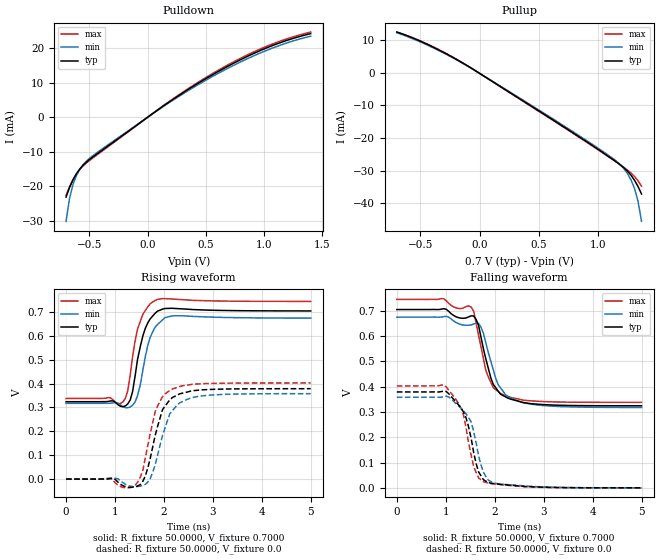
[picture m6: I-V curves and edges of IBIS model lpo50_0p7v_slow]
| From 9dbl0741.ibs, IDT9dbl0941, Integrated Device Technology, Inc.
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|   Model lpo50_0p7v_slow
[Model]  lpo50_0p7v_slow
Model_type Output
Polarity   Non-Inverting
Vmeas =  0.4000V
Cref =   2.0000pF
Rref =   0.0
Vref =   0.4000V
C_comp   1.1000pF   1.0000pF   1.2000pF
[Temperature Range]   27.0000   70.0000   0.0
[Voltage Range]   0.7000V   0.6700V   0.7400V
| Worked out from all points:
|   slope of the pulldown table from 0 to 0.105 V, typ, clamps not added: 41.3 ohm
|   slope of the pullup table from 0 to 0.105 V, typ, clamps not added: 43.4 ohm
|   rising waveform, R_fixture 50.0000, V_fixture 0.7000: 20-80 % time 228ps typ, 231ps min, 222ps max; typ from 0.324 V to 0.705 V
|   rising waveform, R_fixture 50.0000, V_fixture 0.0: 20-80 % time 306ps typ, 336ps min, 300ps max; typ from 0 V to 0.379 V
|   falling waveform, R_fixture 50.0000, V_fixture 0.7000: 20-80 % time 319ps typ, 363ps min, 309ps max; typ from 0.704 V to 0.324 V
|   falling waveform, R_fixture 50.0000, V_fixture 0.0: 20-80 % time 299ps typ, 317ps min, 285ps max; typ from 0.379 V to 0 V
[Pulldown]
|Voltage   I(typ)   I(min)   I(max)
-700mV    -23.07mA   -30.06mA   -22.55mA
-670mV    -20.3mA    -23.39mA   -20.06mA
-640mV    -18.07mA   -19.37mA   -17.97mA
-610mV    -16.28mA   -16.77mA   -16.3mA
-580mV    -14.86mA   -14.94mA   -14.98mA
-550mV    -13.73mA   -13.58mA   -13.94mA
-460mV    -11.23mA   -10.85mA   -11.51mA
200mV     4.757mA    4.547mA    4.904mA
590mV     12.91mA    12.39mA    13.27mA
980mV     19.46mA    18.75mA    19.92mA
1.19V     22.15mA    21.42mA    22.6mA
1.4V      24.16mA    23.42mA    24.62mA
[Pullup]
|Voltage   I(typ)   I(min)   I(max)
-700mV    12.47mA    12.25mA    12.46mA
-430mV    8.493mA    8.28mA     8.576mA
-160mV    3.337mA    3.235mA    3.395mA
590mV     -13.76mA   -13.46mA   -13.9mA
920mV     -21.51mA   -21.16mA   -21.66mA
1.13V     -26.66mA   -26.37mA   -26.76mA
1.22V     -29.12mA   -29.37mA   -29.03mA
1.25V     -30.13mA   -30.86mA   -29.84mA
1.28V     -31.38mA   -32.79mA   -30.73mA
1.31V     -32.94mA   -35.43mA   -31.79mA
1.34V     -34.86mA   -39.33mA   -33.12mA
1.37V     -37.19mA   -45.56mA   -34.8mA
[Ramp]
| variable   typ   min   max
dV/dt_r  0.2273/0.3063n   0.2148/0.3359n   0.2417/0.2998n
dV/dt_f  0.2282/0.3187n   0.2141/0.3633n   0.2441/0.3088n
R_load = 50.0000
[Rising Waveform]
R_fixture= 50.0000
V_fixture= 0.7000
V_fixture_min= 0.6700
V_fixture_max= 0.7400
|time   V(typ)   V(min)   V(max)
0s        324.2mV    317.4mV    337.8mV
960ps     327.6mV    319.7mV    332mV
1.16ns    303.4mV    303.5mV    322.9mV
1.26ns    314.7mV    299mV      369.9mV
1.31ns    331.1mV    302mV      434.7mV
1.46ns    500.6mV    349.2mV    627.8mV
1.67ns    654.5mV    560.4mV    721.7mV
1.87ns    704mV      648mV      753mV
2.22ns    715.1mV    684.5mV    753.9mV
5ns       704.6mV    674.6mV    744.6mV
[Rising Waveform]
R_fixture= 50.0000
V_fixture= 0.0
V_fixture_min= 0.0
V_fixture_max= 0.0
|time   V(typ)   V(min)   V(max)
0s        578.5nV    0V         711.6nV
1.01ns    -2.639mV   3.765mV    -16.71mV
1.41ns    -32.25mV   -32.21mV   -26.14mV
1.57ns    -8.924mV   -26.93mV   38.23mV
1.72ns    86.49mV    1.626mV    190.7mV
1.82ns    182.2mV    58.83mV    281.4mV
1.97ns    290.6mV    181.3mV    345.1mV
2.17ns    341.3mV    286mV      377.4mV
2.73ns    373.1mV    347.5mV    399mV
5ns       378.8mV    358mV      402.8mV
[Falling Waveform]
R_fixture= 50.0000
V_fixture= 0.7000
V_fixture_min= 0.6700
V_fixture_max= 0.7400
|time   V(typ)   V(min)   V(max)
0s        704.5mV    674.4mV    744.6mV
1.01ns    705.5mV    677.7mV    739.3mV
1.52ns    679.7mV    643.6mV    714.2mV
1.57ns    679.1mV    647.6mV    697.9mV
1.67ns    641.8mV    650mV      603.1mV
1.82ns    508.5mV    571.5mV    463.5mV
1.97ns    409.1mV    466.7mV    396.2mV
2.17ns    364.7mV    381.5mV    368.5mV
2.88ns    330.4mV    327.1mV    342.1mV
5ns       324.2mV    317.5mV    337.8mV
[Falling Waveform]
R_fixture= 50.0000
V_fixture= 0.0
V_fixture_min= 0.0
V_fixture_max= 0.0
|time   V(typ)   V(min)   V(max)
0s        378.8mV    358.1mV    402.8mV
1.01ns    380.7mV    362mV      398.3mV
1.36ns    300.6mV    304.6mV    289.3mV
1.52ns    194.4mV    259.9mV    127.8mV
1.57ns    139.1mV    223.2mV    83.96mV
1.67ns    63.07mV    127.3mV    39.32mV
1.77ns    32.14mV    61.52mV    23.67mV
1.87ns    21.91mV    30.24mV    19.06mV
2.17ns    13.02mV    14.09mV    11.72mV
5ns       18.23uV    54.64uV    7.85uV
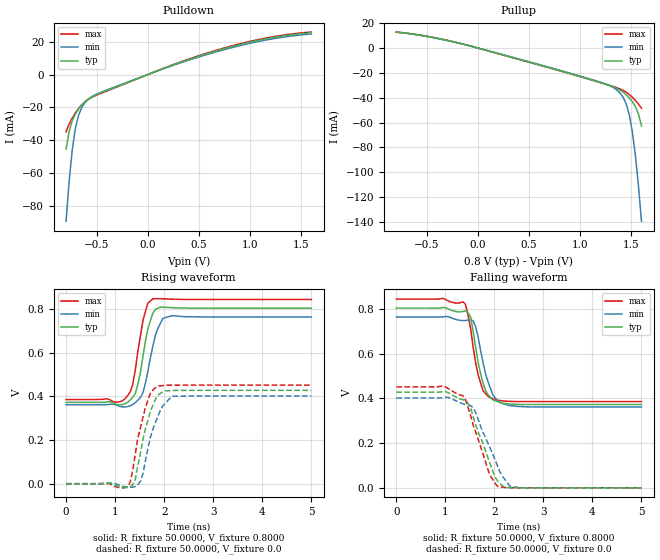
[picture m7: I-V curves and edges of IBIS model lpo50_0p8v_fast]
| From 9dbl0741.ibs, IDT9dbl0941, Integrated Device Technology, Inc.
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|   Model lpo50_0p8v_fast
[Model]  lpo50_0p8v_fast
Model_type Output
Polarity   Non-Inverting
Vmeas =  0.4000V
Cref =   2.0000pF
Rref =   0.0
Vref =   0.4000V
C_comp   1.1000pF   1.0000pF   1.2000pF
[Temperature Range]   27.0000   70.0000   0.0
[Voltage Range]   0.8000V   0.7600V   0.8400V
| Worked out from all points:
|   slope of the pulldown table from 0 to 0.12 V, typ, clamps not added: 41.4 ohm
|   slope of the pullup table from 0 to 0.12 V, typ, clamps not added: 44.4 ohm
|   rising waveform, R_fixture 50.0000, V_fixture 0.8000: 20-80 % time 212ps typ, 229ps min, 196ps max; typ from 0.372 V to 0.804 V
|   rising waveform, R_fixture 50.0000, V_fixture 0.0: 20-80 % time 273ps typ, 299ps min, 256ps max; typ from 0 V to 0.428 V
|   falling waveform, R_fixture 50.0000, V_fixture 0.8000: 20-80 % time 231ps typ, 266ps min, 227ps max; typ from 0.804 V to 0.372 V
|   falling waveform, R_fixture 50.0000, V_fixture 0.0: 20-80 % time 415ps typ, 453ps min, 396ps max; typ from 0.428 V to 0 V
[Pulldown]
|Voltage   I(typ)   I(min)   I(max)
-800mV    -45.52mA   -89.42mA   -34.99mA
-770mV    -34.69mA   -64.98mA   -30.13mA
-740mV    -28.28mA   -46.11mA   -26.53mA
-710mV    -24.18mA   -33.19mA   -23.49mA
-680mV    -21.17mA   -25.25mA   -20.86mA
-650mV    -18.77mA   -20.52mA   -18.63mA
-620mV    -16.84mA   -17.54mA   -16.82mA
-560mV    -14.08mA   -14mA      -14.27mA
100mV     2.426mA    2.317mA    2.503mA
670mV     14.39mA    13.82mA    14.78mA
1.15V     21.69mA    20.96mA    22.14mA
1.6V      25.43mA    24.71mA    25.88mA
[Pullup]
|Voltage   I(typ)   I(min)   I(max)
-800mV    12.69mA    12.68mA    12.51mA
-440mV    8.345mA    8.179mA    8.402mA
-20mV     274.7uA    267.5uA    282.2uA
1.15V     -26.68mA   -26.4mA    -26.75mA
1.36V     -32.54mA   -33.95mA   -32.08mA
1.42V     -35.56mA   -39.7mA    -34.16mA
1.45V     -37.62mA   -44.96mA   -35.6mA
1.48V     -40.1mA    -53.57mA   -37.41mA
1.51V     -43.12mA   -67.09mA   -39.62mA
1.54V     -47.08mA   -86.23mA   -42.2mA
1.57V     -53mA      -110.6mA   -45.14mA
1.6V      -62.75mA   -139.3mA   -48.48mA
[Ramp]
| variable   typ   min   max
dV/dt_r  0.2567/0.2641n   0.2412/0.2994n   0.2710/0.2465n
dV/dt_f  0.2590/0.2314n   0.2414/0.2657n   0.2750/0.2205n
R_load = 50.0000
[Rising Waveform]
R_fixture= 50.0000
V_fixture= 0.8000
V_fixture_min= 0.7600
V_fixture_max= 0.8400
|time   V(typ)   V(min)   V(max)
0s        372.5mV    361.7mV    385.7mV
1.21ns    366.7mV    352.2mV    391.5mV
1.36ns    396.9mV    362.9mV    456.1mV
1.46ns    452.4mV    382mV      601.3mV
1.57ns    586.6mV    418.2mV    749.7mV
1.67ns    712.4mV    516.9mV    828mV
1.77ns    781.9mV    631.5mV    847.1mV
1.97ns    808.9mV    756.4mV    847.4mV
2.17ns    806.4mV    770.1mV    845.2mV
5ns       804.1mV    764mV      844.1mV
[Rising Waveform]
R_fixture= 50.0000
V_fixture= 0.0
V_fixture_min= 0.0
V_fixture_max= 0.0
|time   V(typ)   V(min)   V(max)
0s        0V         0V         0V
1.26ns    -17.13mV   -16.18mV   -11.84mV
1.31ns    -13.73mV   -16.75mV   9.189mV
1.41ns    19.42mV    -13.04mV   134.2mV
1.52ns    145.8mV    12.61mV    260.3mV
1.72ns    331.2mV    213.7mV    414.4mV
1.87ns    405.9mV    308mV      447.2mV
1.97ns    420.8mV    356.2mV    449.4mV
2.17ns    426.9mV    400.6mV    451.4mV
5ns       427.8mV    402mV      451.7mV
[Falling Waveform]
R_fixture= 50.0000
V_fixture= 0.8000
V_fixture_min= 0.7600
V_fixture_max= 0.8400
|time   V(typ)   V(min)   V(max)
0s        804.1mV    764mV      844.1mV
960ps     806.9mV    765.3mV    846.5mV
1.41ns    791.7mV    748.4mV    821.2mV
1.52ns    761.2mV    752mV      706.4mV
1.62ns    627.5mV    718.4mV    557.3mV
1.72ns    510mV      613.5mV    468.3mV
1.87ns    416.2mV    474.9mV    409.4mV
2.02ns    389.1mV    401.9mV    393.7mV
2.53ns    372.9mV    363.4mV    385.8mV
5ns       372.5mV    361.7mV    385.7mV
[Falling Waveform]
R_fixture= 50.0000
V_fixture= 0.0
V_fixture_min= 0.0
V_fixture_max= 0.0
|time   V(typ)   V(min)   V(max)
0s        427.8mV    402mV      451.7mV
960ps     431.2mV    403.4mV    455mV
1.36ns    393.8mV    375.9mV    412mV
1.46ns    379.8mV    370mV      361.4mV
1.57ns    316.3mV    357.6mV    279.4mV
1.87ns    133.7mV    199.5mV    80.29mV
2.07ns    28.79mV    94.97mV    5.84mV
2.17ns    8.971mV    50.22mV    2.647mV
2.37ns    814.5uV    4.553mV    70.06uV
5ns       616.5nV    1.697uV    1.177uV
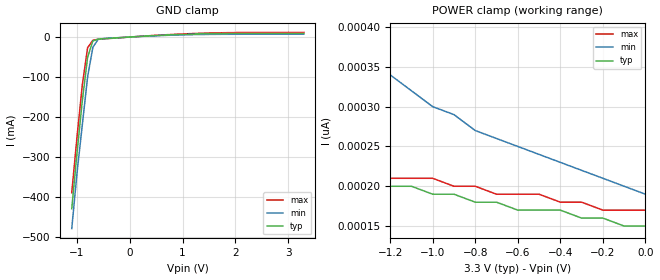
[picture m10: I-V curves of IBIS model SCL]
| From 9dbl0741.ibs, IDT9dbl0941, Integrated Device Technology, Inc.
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|   Model SCL
[Model]   SCL
Model_type   Input
Polarity   Inverting
Enable   Active-High
Vinl =   0.80V
Vinh =   2.00V
C_comp   3.40pF   2.85pF   3.95pF
[Temperature Range]   27.00   70.00   0.000
[Voltage Range]   3.30V   3.00V   3.70V
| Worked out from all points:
|   GND clamp passes 1 mA (typ) near -0.12 V on its own axis
[GND_clamp]
| voltage   I(typ)   I(min)   I(max)
| -3.30   -3.78A   -3.64A   -3.87A
| -3.20   -3.62A   -3.50A   -3.71A
| -3.10   -3.47A   -3.35A   -3.55A
| -3.00   -3.31A   -3.21A   -3.39A
| -2.90   -3.16A   -3.06A   -3.23A
| -2.80   -3.01A   -2.91A   -3.07A
| -2.70   -2.85A   -2.77A   -2.91A
| -2.60   -2.70A   -2.62A   -2.75A
| -2.50   -2.54A   -2.48A   -2.59A
| -2.40   -2.39A   -2.33A   -2.43A
| -2.30   -2.24A   -2.19A   -2.27A
| -2.20   -2.08A   -2.04A   -2.11A
| -2.10   -1.93A   -1.90A   -1.95A
| -2.00   -1.78A   -1.75A   -1.79A
| -1.90   -1.62A   -1.61A   -1.63A
| -1.80   -1.47A   -1.46A   -1.47A
| -1.70   -1.32A   -1.32A   -1.32A
| -1.60   -1.17A   -1.18A   -1.16A
| -1.50   -1.02A   -1.03A   -1.00A
| -1.40   -0.87A   -0.89A   -0.85A
| -1.30   -0.72A   -0.75A   -0.69A
| -1.20   -0.57A   -0.61A   -0.54A
-1.1V     -430mA     -480mA     -390mA
-1V       -290mA     -340mA     -250mA
-900mV    -160mA     -220mA     -120mA
-800mV    -50.98mA   -100mA     -26.96mA
-700mV    -9.68mA    -25.77mA   -7.88mA
-600mV    -5.33mA    -5.93mA    -5.67mA
300mV     2.39mA     2.03mA     2.7mA
1.3V      7.73mA     6.23mA     9.22mA
3.3V      9.23mA     7.24mA     11.63mA
[POWER_clamp]
| voltage   I(typ)   I(min)   I(max)
-3.3V     350pA      1.67nA     310pA
-2.6V     280pA      890pA      270pA
-2.5V     280pA      820pA      270pA
-2.4V     270pA      750pA      260pA
-2.2V     250pA      640pA      260pA
-1.7V     230pA      450pA      230pA
-1.5V     220pA      400pA      230pA
-1.4V     210pA      380pA      220pA
-1V       190pA      300pA      210pA
-800mV    180pA      270pA      200pA
-200mV    160pA      210pA      170pA
0V        150pA      190pA      170pA
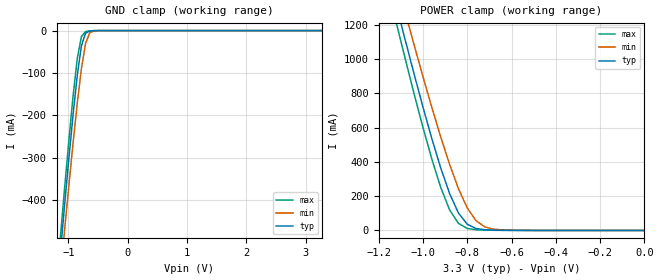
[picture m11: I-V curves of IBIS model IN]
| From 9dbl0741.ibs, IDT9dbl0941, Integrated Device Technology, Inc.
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|   Model IN
[Model]  IN
Model_type Input
Polarity   Inverting
Vinl =   0.8000V
Vinh =   2.0000V
C_comp   1.1000pF   1.0000pF   1.2000pF
[Temperature Range]   27.0000   70.0000   0.0
[Voltage Range]   3.3000V   3.0000V   3.6000V
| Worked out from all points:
|   GND clamp passes 1 mA (typ) near -0.63 V on its own axis
|   POWER clamp passes 1 mA (typ) near -0.62 V on its own axis
[GND_clamp]
|Voltage   I(typ)   I(min)   I(max)
-3.3V     -4.157A    -4.009A    -4.256A
-1.13V    -515.4mA   -568.9mA   -479.1mA
-1.06V    -405.7mA   -464.7mA   -365.7mA
-990mV    -299mA     -362.7mA   -256.1mA
-920mV    -197.3mA   -264.1mA   -153.4mA
-850mV    -105.5mA   -171.3mA   -65.69mA
-780mV    -35.72mA   -89.29mA   -13.97mA
-710mV    -6.148mA   -29.96mA   -2.292mA
-640mV    -1.065mA   -5.517mA   -522.5uA
-570mV    -210.9uA   -872uA     -98.27uA
-500mV    -36.29uA   -147.4uA   -14.75uA
3.28V     -777.2pA   16.94uA    -290.6pA
[POWER_clamp]
|Voltage   I(typ)   I(min)   I(max)
-3.28V    13.24A     12.73A     13.56A
-1.12V    1.311A     1.463A     1.207A
-1.08V    1.109A     1.27A      999mA
-1.04V    910.9mA    1.081A     795.6mA
-960mV    535.1mA    716.8mA    415.9mA
-920mV    364.8mA    545.5mA    251.5mA
-880mV    215.9mA    385.9mA    120.6mA
-840mV    102.1mA    244.5mA    41.54mA
-800mV    36.36mA    131mA      11.68mA
-760mV    11.29mA    56.34mA    4.01mA
-680mV    2.07mA     7.399mA    1.193mA
0V        153.8pA    201.6pA    165.7pA
